VERSION 5.8 ;
BUSBITCHARS "[]" ;
DIVIDERCHAR "/" ;
UNITS
    DATABASE MICRONS 1000 ;
END UNITS

VIA PLL_COUNTER_DCO_PHYS_via1_2_2200_440_1_5_410_410
  VIARULE via1Array ;
  CUTSIZE 0.19 0.19 ;
  LAYERS Metal1 Via1 Metal2 ;
  CUTSPACING 0.22 0.22 ;
  ENCLOSURE 0.05 0.125 0.005 0.05 ;
  ROWCOL 1 5 ;
END PLL_COUNTER_DCO_PHYS_via1_2_2200_440_1_5_410_410

VIA PLL_COUNTER_DCO_PHYS_via2_3_2200_440_1_5_410_410
  VIARULE via2Array ;
  CUTSIZE 0.19 0.19 ;
  LAYERS Metal2 Via2 Metal3 ;
  CUTSPACING 0.22 0.22 ;
  ENCLOSURE 0.005 0.05 0.05 0.005 ;
  ROWCOL 1 5 ;
END PLL_COUNTER_DCO_PHYS_via2_3_2200_440_1_5_410_410

VIA PLL_COUNTER_DCO_PHYS_via3_4_2200_440_1_5_410_410
  VIARULE via3Array ;
  CUTSIZE 0.19 0.19 ;
  LAYERS Metal3 Via3 Metal4 ;
  CUTSPACING 0.22 0.22 ;
  ENCLOSURE 0.05 0.005 0.005 0.05 ;
  ROWCOL 1 5 ;
END PLL_COUNTER_DCO_PHYS_via3_4_2200_440_1_5_410_410

VIA PLL_COUNTER_DCO_PHYS_via4_5_2200_440_1_5_410_410
  VIARULE via4Array ;
  CUTSIZE 0.19 0.19 ;
  LAYERS Metal4 Via4 Metal5 ;
  CUTSPACING 0.22 0.22 ;
  ENCLOSURE 0.005 0.05 0.05 0.005 ;
  ROWCOL 1 5 ;
END PLL_COUNTER_DCO_PHYS_via4_5_2200_440_1_5_410_410

VIA PLL_COUNTER_DCO_PHYS_via5_6_2200_440_1_2_840_840
  VIARULE viaTop1Array ;
  CUTSIZE 0.42 0.42 ;
  LAYERS Metal5 TopVia1 TopMetal1 ;
  CUTSPACING 0.42 0.42 ;
  ENCLOSURE 0.1 0.1 0.47 0.42 ;
  ROWCOL 1 2 ;
END PLL_COUNTER_DCO_PHYS_via5_6_2200_440_1_2_840_840

VIA PLL_COUNTER_DCO_PHYS_via6_7_5000_5000_2_2_1960_1960
  VIARULE viaTop2Array ;
  CUTSIZE 0.9 0.9 ;
  LAYERS TopMetal1 TopVia2 TopMetal2 ;
  CUTSPACING 1.06 1.06 ;
  ENCLOSURE 1.07 0.5 0.5 1.07 ;
  ROWCOL 2 2 ;
END PLL_COUNTER_DCO_PHYS_via6_7_5000_5000_2_2_1960_1960

VIA PLL_COUNTER_DCO_PHYS_via6_7_5000_2200_1_2_1960_1960
  VIARULE viaTop2Array ;
  CUTSIZE 0.9 0.9 ;
  LAYERS TopMetal1 TopVia2 TopMetal2 ;
  CUTSPACING 1.06 1.06 ;
  ENCLOSURE 1.07 0.5 0.5 0.65 ;
  ROWCOL 1 2 ;
END PLL_COUNTER_DCO_PHYS_via6_7_5000_2200_1_2_1960_1960

VIA PLL_COUNTER_DCO_PHYS_via6_7_2200_5000_2_1_1960_1960
  VIARULE viaTop2Array ;
  CUTSIZE 0.9 0.9 ;
  LAYERS TopMetal1 TopVia2 TopMetal2 ;
  CUTSPACING 1.06 1.06 ;
  ENCLOSURE 0.65 0.5 0.5 1.07 ;
  ROWCOL 2 1 ;
END PLL_COUNTER_DCO_PHYS_via6_7_2200_5000_2_1_1960_1960

VIA PLL_COUNTER_DCO_PHYS_via6_7_2200_2200_1_1_1960_1960
  VIARULE viaTop2Array ;
  CUTSIZE 0.9 0.9 ;
  LAYERS TopMetal1 TopVia2 TopMetal2 ;
  CUTSPACING 1.06 1.06 ;
  ENCLOSURE 0.65 0.5 0.5 0.65 ;
END PLL_COUNTER_DCO_PHYS_via6_7_2200_2200_1_1_1960_1960

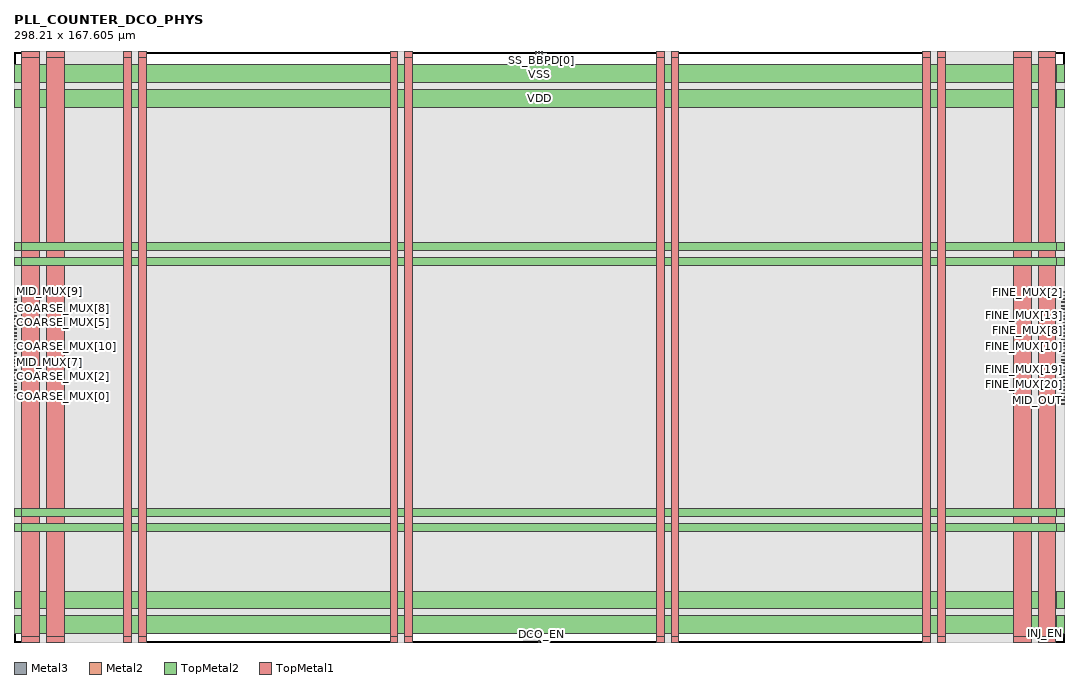
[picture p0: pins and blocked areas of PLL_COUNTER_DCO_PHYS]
MACRO PLL_COUNTER_DCO_PHYS
  FOREIGN PLL_COUNTER_DCO_PHYS 0 0 ;
  CLASS BLOCK ;
  SIZE 298.21 BY 167.605 ;
  PIN COARSE_MUX[0]
    DIRECTION INPUT ;
    USE SIGNAL ;
    PORT
      LAYER Metal3 ;
        RECT  0 69.5 0.72 69.7 ;
    END
  END COARSE_MUX[0]
  PIN COARSE_MUX[10]
    DIRECTION INPUT ;
    USE SIGNAL ;
    PORT
      LAYER Metal3 ;
        RECT  0 83.9 0.72 84.1 ;
    END
  END COARSE_MUX[10]
  PIN COARSE_MUX[11]
    DIRECTION INPUT ;
    USE SIGNAL ;
    PORT
      LAYER Metal3 ;
        RECT  0 76.22 0.72 76.42 ;
    END
  END COARSE_MUX[11]
  PIN COARSE_MUX[12]
    DIRECTION INPUT ;
    USE SIGNAL ;
    PORT
      LAYER Metal3 ;
        RECT  0 80.06 0.72 80.26 ;
    END
  END COARSE_MUX[12]
  PIN COARSE_MUX[13]
    DIRECTION INPUT ;
    USE SIGNAL ;
    PORT
      LAYER Metal3 ;
        RECT  0 72.38 0.72 72.58 ;
    END
  END COARSE_MUX[13]
  PIN COARSE_MUX[14]
    DIRECTION INPUT ;
    USE SIGNAL ;
    PORT
      LAYER Metal3 ;
        RECT  0 86.78 0.72 86.98 ;
    END
  END COARSE_MUX[14]
  PIN COARSE_MUX[1]
    DIRECTION INPUT ;
    USE SIGNAL ;
    PORT
      LAYER Metal3 ;
        RECT  0 87.74 0.72 87.94 ;
    END
  END COARSE_MUX[1]
  PIN COARSE_MUX[2]
    DIRECTION INPUT ;
    USE SIGNAL ;
    PORT
      LAYER Metal3 ;
        RECT  0 75.26 0.72 75.46 ;
    END
  END COARSE_MUX[2]
  PIN COARSE_MUX[3]
    DIRECTION INPUT ;
    USE SIGNAL ;
    PORT
      LAYER Metal3 ;
        RECT  0 88.7 0.72 88.9 ;
    END
  END COARSE_MUX[3]
  PIN COARSE_MUX[4]
    DIRECTION INPUT ;
    USE SIGNAL ;
    PORT
      LAYER Metal3 ;
        RECT  0 89.66 0.72 89.86 ;
    END
  END COARSE_MUX[4]
  PIN COARSE_MUX[5]
    DIRECTION INPUT ;
    USE SIGNAL ;
    PORT
      LAYER Metal3 ;
        RECT  0 90.62 0.72 90.82 ;
    END
  END COARSE_MUX[5]
  PIN COARSE_MUX[6]
    DIRECTION INPUT ;
    USE SIGNAL ;
    PORT
      LAYER Metal3 ;
        RECT  0 81.02 0.72 81.22 ;
    END
  END COARSE_MUX[6]
  PIN COARSE_MUX[7]
    DIRECTION INPUT ;
    USE SIGNAL ;
    PORT
      LAYER Metal3 ;
        RECT  0 74.3 0.72 74.5 ;
    END
  END COARSE_MUX[7]
  PIN COARSE_MUX[8]
    DIRECTION INPUT ;
    USE SIGNAL ;
    PORT
      LAYER Metal3 ;
        RECT  0 92.54 0.72 92.74 ;
    END
  END COARSE_MUX[8]
  PIN COARSE_MUX[9]
    DIRECTION INPUT ;
    USE SIGNAL ;
    PORT
      LAYER Metal3 ;
        RECT  0 85.82 0.72 86.02 ;
    END
  END COARSE_MUX[9]
  PIN DCO_EN
    DIRECTION INPUT ;
    USE SIGNAL ;
    PORT
      LAYER Metal2 ;
        RECT  149.84 0 150.04 0.72 ;
    END
  END DCO_EN
  PIN FINE_MUX[0]
    DIRECTION INPUT ;
    USE SIGNAL ;
    PORT
      LAYER Metal3 ;
        RECT  297.49 67.58 298.21 67.78 ;
    END
  END FINE_MUX[0]
  PIN FINE_MUX[10]
    DIRECTION INPUT ;
    USE SIGNAL ;
    PORT
      LAYER Metal3 ;
        RECT  297.49 83.9 298.21 84.1 ;
    END
  END FINE_MUX[10]
  PIN FINE_MUX[11]
    DIRECTION INPUT ;
    USE SIGNAL ;
    PORT
      LAYER Metal3 ;
        RECT  297.49 98.3 298.21 98.5 ;
    END
  END FINE_MUX[11]
  PIN FINE_MUX[12]
    DIRECTION INPUT ;
    USE SIGNAL ;
    PORT
      LAYER Metal3 ;
        RECT  297.49 96.38 298.21 96.58 ;
    END
  END FINE_MUX[12]
  PIN FINE_MUX[13]
    DIRECTION INPUT ;
    USE SIGNAL ;
    PORT
      LAYER Metal3 ;
        RECT  297.49 92.54 298.21 92.74 ;
    END
  END FINE_MUX[13]
  PIN FINE_MUX[14]
    DIRECTION INPUT ;
    USE SIGNAL ;
    PORT
      LAYER Metal3 ;
        RECT  297.49 84.86 298.21 85.06 ;
    END
  END FINE_MUX[14]
  PIN FINE_MUX[15]
    DIRECTION INPUT ;
    USE SIGNAL ;
    PORT
      LAYER Metal3 ;
        RECT  297.49 87.74 298.21 87.94 ;
    END
  END FINE_MUX[15]
  PIN FINE_MUX[16]
    DIRECTION INPUT ;
    USE SIGNAL ;
    PORT
      LAYER Metal3 ;
        RECT  297.49 79.1 298.21 79.3 ;
    END
  END FINE_MUX[16]
  PIN FINE_MUX[17]
    DIRECTION INPUT ;
    USE SIGNAL ;
    PORT
      LAYER Metal3 ;
        RECT  297.49 78.14 298.21 78.34 ;
    END
  END FINE_MUX[17]
  PIN FINE_MUX[18]
    DIRECTION INPUT ;
    USE SIGNAL ;
    PORT
      LAYER Metal3 ;
        RECT  297.49 93.5 298.21 93.7 ;
    END
  END FINE_MUX[18]
  PIN FINE_MUX[19]
    DIRECTION INPUT ;
    USE SIGNAL ;
    PORT
      LAYER Metal3 ;
        RECT  297.49 77.18 298.21 77.38 ;
    END
  END FINE_MUX[19]
  PIN FINE_MUX[1]
    DIRECTION INPUT ;
    USE SIGNAL ;
    PORT
      LAYER Metal3 ;
        RECT  297.49 76.22 298.21 76.42 ;
    END
  END FINE_MUX[1]
  PIN FINE_MUX[20]
    DIRECTION INPUT ;
    USE SIGNAL ;
    PORT
      LAYER Metal3 ;
        RECT  297.49 75.26 298.21 75.46 ;
    END
  END FINE_MUX[20]
  PIN FINE_MUX[21]
    DIRECTION INPUT ;
    USE SIGNAL ;
    PORT
      LAYER Metal3 ;
        RECT  297.49 86.78 298.21 86.98 ;
    END
  END FINE_MUX[21]
  PIN FINE_MUX[22]
    DIRECTION INPUT ;
    USE SIGNAL ;
    PORT
      LAYER Metal3 ;
        RECT  297.49 82.94 298.21 83.14 ;
    END
  END FINE_MUX[22]
  PIN FINE_MUX[23]
    DIRECTION INPUT ;
    USE SIGNAL ;
    PORT
      LAYER Metal3 ;
        RECT  297.49 94.46 298.21 94.66 ;
    END
  END FINE_MUX[23]
  PIN FINE_MUX[24]
    DIRECTION INPUT ;
    USE SIGNAL ;
    PORT
      LAYER Metal3 ;
        RECT  297.49 81.98 298.21 82.18 ;
    END
  END FINE_MUX[24]
  PIN FINE_MUX[25]
    DIRECTION INPUT ;
    USE SIGNAL ;
    PORT
      LAYER Metal3 ;
        RECT  297.49 97.34 298.21 97.54 ;
    END
  END FINE_MUX[25]
  PIN FINE_MUX[26]
    DIRECTION INPUT ;
    USE SIGNAL ;
    PORT
      LAYER Metal3 ;
        RECT  297.49 72.38 298.21 72.58 ;
    END
  END FINE_MUX[26]
  PIN FINE_MUX[27]
    DIRECTION INPUT ;
    USE SIGNAL ;
    PORT
      LAYER Metal3 ;
        RECT  297.49 71.42 298.21 71.62 ;
    END
  END FINE_MUX[27]
  PIN FINE_MUX[28]
    DIRECTION INPUT ;
    USE SIGNAL ;
    PORT
      LAYER Metal3 ;
        RECT  297.49 70.46 298.21 70.66 ;
    END
  END FINE_MUX[28]
  PIN FINE_MUX[29]
    DIRECTION INPUT ;
    USE SIGNAL ;
    PORT
      LAYER Metal3 ;
        RECT  297.49 88.7 298.21 88.9 ;
    END
  END FINE_MUX[29]
  PIN FINE_MUX[2]
    DIRECTION INPUT ;
    USE SIGNAL ;
    PORT
      LAYER Metal3 ;
        RECT  297.49 99.26 298.21 99.46 ;
    END
  END FINE_MUX[2]
  PIN FINE_MUX[30]
    DIRECTION INPUT ;
    USE SIGNAL ;
    PORT
      LAYER Metal3 ;
        RECT  297.49 80.06 298.21 80.26 ;
    END
  END FINE_MUX[30]
  PIN FINE_MUX[3]
    DIRECTION INPUT ;
    USE SIGNAL ;
    PORT
      LAYER Metal3 ;
        RECT  297.49 95.42 298.21 95.62 ;
    END
  END FINE_MUX[3]
  PIN FINE_MUX[4]
    DIRECTION INPUT ;
    USE SIGNAL ;
    PORT
      LAYER Metal3 ;
        RECT  297.49 89.66 298.21 89.86 ;
    END
  END FINE_MUX[4]
  PIN FINE_MUX[5]
    DIRECTION INPUT ;
    USE SIGNAL ;
    PORT
      LAYER Metal3 ;
        RECT  297.49 81.02 298.21 81.22 ;
    END
  END FINE_MUX[5]
  PIN FINE_MUX[6]
    DIRECTION INPUT ;
    USE SIGNAL ;
    PORT
      LAYER Metal3 ;
        RECT  297.49 69.5 298.21 69.7 ;
    END
  END FINE_MUX[6]
  PIN FINE_MUX[7]
    DIRECTION INPUT ;
    USE SIGNAL ;
    PORT
      LAYER Metal3 ;
        RECT  297.49 73.34 298.21 73.54 ;
    END
  END FINE_MUX[7]
  PIN FINE_MUX[8]
    DIRECTION INPUT ;
    USE SIGNAL ;
    PORT
      LAYER Metal3 ;
        RECT  297.49 90.62 298.21 90.82 ;
    END
  END FINE_MUX[8]
  PIN FINE_MUX[9]
    DIRECTION INPUT ;
    USE SIGNAL ;
    PORT
      LAYER Metal3 ;
        RECT  297.49 74.3 298.21 74.5 ;
    END
  END FINE_MUX[9]
  PIN INJ_EN
    DIRECTION INPUT ;
    USE SIGNAL ;
    PORT
      LAYER Metal3 ;
        RECT  297.49 2.3 298.21 2.5 ;
    END
  END INJ_EN
  PIN MID_MUX[0]
    DIRECTION INPUT ;
    USE SIGNAL ;
    PORT
      LAYER Metal3 ;
        RECT  0 70.46 0.72 70.66 ;
    END
  END MID_MUX[0]
  PIN MID_MUX[10]
    DIRECTION INPUT ;
    USE SIGNAL ;
    PORT
      LAYER Metal3 ;
        RECT  0 91.58 0.72 91.78 ;
    END
  END MID_MUX[10]
  PIN MID_MUX[11]
    DIRECTION INPUT ;
    USE SIGNAL ;
    PORT
      LAYER Metal3 ;
        RECT  0 71.42 0.72 71.62 ;
    END
  END MID_MUX[11]
  PIN MID_MUX[12]
    DIRECTION INPUT ;
    USE SIGNAL ;
    PORT
      LAYER Metal3 ;
        RECT  0 95.42 0.72 95.62 ;
    END
  END MID_MUX[12]
  PIN MID_MUX[13]
    DIRECTION INPUT ;
    USE SIGNAL ;
    PORT
      LAYER Metal3 ;
        RECT  0 79.1 0.72 79.3 ;
    END
  END MID_MUX[13]
  PIN MID_MUX[14]
    DIRECTION INPUT ;
    USE SIGNAL ;
    PORT
      LAYER Metal3 ;
        RECT  0 84.86 0.72 85.06 ;
    END
  END MID_MUX[14]
  PIN MID_MUX[1]
    DIRECTION INPUT ;
    USE SIGNAL ;
    PORT
      LAYER Metal3 ;
        RECT  0 73.34 0.72 73.54 ;
    END
  END MID_MUX[1]
  PIN MID_MUX[2]
    DIRECTION INPUT ;
    USE SIGNAL ;
    PORT
      LAYER Metal3 ;
        RECT  0 93.5 0.72 93.7 ;
    END
  END MID_MUX[2]
  PIN MID_MUX[3]
    DIRECTION INPUT ;
    USE SIGNAL ;
    PORT
      LAYER Metal3 ;
        RECT  0 78.14 0.72 78.34 ;
    END
  END MID_MUX[3]
  PIN MID_MUX[4]
    DIRECTION INPUT ;
    USE SIGNAL ;
    PORT
      LAYER Metal3 ;
        RECT  0 96.38 0.72 96.58 ;
    END
  END MID_MUX[4]
  PIN MID_MUX[5]
    DIRECTION INPUT ;
    USE SIGNAL ;
    PORT
      LAYER Metal3 ;
        RECT  0 94.46 0.72 94.66 ;
    END
  END MID_MUX[5]
  PIN MID_MUX[6]
    DIRECTION INPUT ;
    USE SIGNAL ;
    PORT
      LAYER Metal3 ;
        RECT  0 82.94 0.72 83.14 ;
    END
  END MID_MUX[6]
  PIN MID_MUX[7]
    DIRECTION INPUT ;
    USE SIGNAL ;
    PORT
      LAYER Metal3 ;
        RECT  0 77.18 0.72 77.38 ;
    END
  END MID_MUX[7]
  PIN MID_MUX[8]
    DIRECTION INPUT ;
    USE SIGNAL ;
    PORT
      LAYER Metal3 ;
        RECT  0 81.98 0.72 82.18 ;
    END
  END MID_MUX[8]
  PIN MID_MUX[9]
    DIRECTION INPUT ;
    USE SIGNAL ;
    PORT
      LAYER Metal3 ;
        RECT  0 97.34 0.72 97.54 ;
    END
  END MID_MUX[9]
  PIN MID_OUT
    DIRECTION OUTPUT ;
    USE SIGNAL ;
    PORT
      LAYER Metal3 ;
        RECT  297.49 68.54 298.21 68.74 ;
    END
  END MID_OUT
  PIN OUT
    DIRECTION OUTPUT ;
    USE SIGNAL ;
    PORT
      LAYER Metal3 ;
        RECT  297.49 85.82 298.21 86.02 ;
    END
  END OUT
  PIN INJ_EDGE
    DIRECTION OUTPUT ;
    USE SIGNAL ;
    PORT
      LAYER Metal3 ;
        RECT  297.49 91.58 298.21 91.78 ;
    END
  END INJ_EDGE
  PIN REF
    DIRECTION INPUT ;
    USE SIGNAL ;
    PORT
      LAYER Metal2 ;
        RECT  149 0 149.2 0.72 ;
    END
  END REF
  PIN SS_BBPD[0]
    DIRECTION OUTPUT ;
    USE SIGNAL ;
    PORT
      LAYER Metal2 ;
        RECT  149.84 166.885 150.04 167.605 ;
    END
  END SS_BBPD[0]
  PIN SS_BBPD[1]
    DIRECTION OUTPUT ;
    USE SIGNAL ;
    PORT
      LAYER Metal2 ;
        RECT  149 166.885 149.2 167.605 ;
    END
  END SS_BBPD[1]
  PIN TICK
    DIRECTION INPUT ;
    USE SIGNAL ;
    PORT
      LAYER Metal2 ;
        RECT  148.16 166.885 148.36 167.605 ;
    END
  END TICK
  PIN VSS
    DIRECTION INOUT ;
    USE GROUND ;
    PORT
      LAYER TopMetal2 ;
        RECT  296.21 111.2 298.21 113.4 ;
        RECT  0 111.2 2 113.4 ;
        RECT  0 111.2 298.21 113.4 ;
        RECT  296.21 35.6 298.21 37.8 ;
        RECT  0 35.6 2 37.8 ;
        RECT  0 35.6 298.21 37.8 ;
      LAYER TopMetal1 ;
        RECT  262.22 165.965 264.42 167.605 ;
        RECT  262.22 0 264.42 1.64 ;
        RECT  262.22 0 264.42 167.605 ;
        RECT  186.62 165.965 188.82 167.605 ;
        RECT  186.62 0 188.82 1.64 ;
        RECT  186.62 0 188.82 167.605 ;
        RECT  111.02 165.965 113.22 167.605 ;
        RECT  111.02 0 113.22 1.64 ;
        RECT  111.02 0 113.22 167.605 ;
        RECT  35.42 165.965 37.62 167.605 ;
        RECT  35.42 0 37.62 1.64 ;
        RECT  35.42 0 37.62 167.605 ;
      LAYER TopMetal2 ;
        RECT  296.21 158.92 298.21 163.92 ;
        RECT  0 158.92 2 163.92 ;
        RECT  0 158.92 298.21 163.92 ;
        RECT  296.21 2.4 298.21 7.4 ;
        RECT  0 2.4 2 7.4 ;
        RECT  0 2.4 298.21 7.4 ;
      LAYER TopMetal1 ;
        RECT  290.86 165.965 295.86 167.605 ;
        RECT  290.86 0 295.86 1.64 ;
        RECT  290.86 0 295.86 167.605 ;
        RECT  2.22 165.965 7.22 167.605 ;
        RECT  2.22 0 7.22 1.64 ;
        RECT  2.22 0 7.22 167.605 ;
    END
  END VSS
  PIN VDD
    DIRECTION INOUT ;
    USE POWER ;
    PORT
      LAYER TopMetal2 ;
        RECT  296.21 107 298.21 109.2 ;
        RECT  0 107 2 109.2 ;
        RECT  0 107 298.21 109.2 ;
        RECT  296.21 31.4 298.21 33.6 ;
        RECT  0 31.4 2 33.6 ;
        RECT  0 31.4 298.21 33.6 ;
      LAYER TopMetal1 ;
        RECT  258.02 165.965 260.22 167.605 ;
        RECT  258.02 0 260.22 1.64 ;
        RECT  258.02 0 260.22 167.605 ;
        RECT  182.42 165.965 184.62 167.605 ;
        RECT  182.42 0 184.62 1.64 ;
        RECT  182.42 0 184.62 167.605 ;
        RECT  106.82 165.965 109.02 167.605 ;
        RECT  106.82 0 109.02 1.64 ;
        RECT  106.82 0 109.02 167.605 ;
        RECT  31.22 165.965 33.42 167.605 ;
        RECT  31.22 0 33.42 1.64 ;
        RECT  31.22 0 33.42 167.605 ;
      LAYER TopMetal2 ;
        RECT  296.21 151.92 298.21 156.92 ;
        RECT  0 151.92 2 156.92 ;
        RECT  0 151.92 298.21 156.92 ;
        RECT  296.21 9.4 298.21 14.4 ;
        RECT  0 9.4 2 14.4 ;
        RECT  0 9.4 298.21 14.4 ;
      LAYER TopMetal1 ;
        RECT  283.86 165.965 288.86 167.605 ;
        RECT  283.86 0 288.86 1.64 ;
        RECT  283.86 0 288.86 167.605 ;
        RECT  9.22 165.965 14.22 167.605 ;
        RECT  9.22 0 14.22 1.64 ;
        RECT  9.22 0 14.22 167.605 ;
    END
  END VDD
  OBS
    LAYER Metal1 ;
     RECT  18.72 18.68 279.36 147.64 ;
    LAYER Metal2 ;
     RECT  144.8 0.38 148.78 0.48 ;
     RECT  186.8 18.755 188.64 20.505 ;
     RECT  57.965 20.49 58.165 20.54 ;
     RECT  70.965 20.53 71.165 20.54 ;
     RECT  186.8 20.505 190.755 20.54 ;
     RECT  216.475 20.505 216.675 20.54 ;
     RECT  250.885 20.51 251.085 20.54 ;
     RECT  262.4 18.755 264.24 20.54 ;
     RECT  57.44 20.54 58.165 20.55 ;
     RECT  262.4 20.54 268.06 20.55 ;
     RECT  166.64 20.54 175.24 20.555 ;
     RECT  204.44 20.54 206.53 20.555 ;
     RECT  57.44 20.55 59.32 21.02 ;
     RECT  69.62 20.54 71.165 21.02 ;
     RECT  144.8 0.48 150.04 21.02 ;
     RECT  203.95 20.555 206.53 21.02 ;
     RECT  216.475 20.54 219.34 21.02 ;
     RECT  57.44 21.02 71.165 21.03 ;
     RECT  166.03 20.555 175.24 21.03 ;
     RECT  242.24 20.54 251.085 21.03 ;
     RECT  186.8 20.54 192.04 21.5 ;
     RECT  203.95 21.02 219.34 21.5 ;
     RECT  242.24 21.03 252.1 21.98 ;
     RECT  262.4 20.55 268.48 22.46 ;
     RECT  35.6 18.755 37.44 22.535 ;
     RECT  111.2 18.755 113.04 22.535 ;
     RECT  166.03 21.03 176.92 22.535 ;
     RECT  186.8 21.5 219.34 22.535 ;
     RECT  240.56 21.98 252.1 22.535 ;
     RECT  262.4 22.46 278.98 22.535 ;
     RECT  144.8 21.02 152.14 22.94 ;
     RECT  31.4 22.535 37.44 22.95 ;
     RECT  57.44 21.03 71.5 23.42 ;
     RECT  140.18 22.94 154.24 23.42 ;
     RECT  166.03 22.535 219.34 23.42 ;
     RECT  140.18 23.42 219.34 23.43 ;
     RECT  57.44 23.42 73.6 23.665 ;
     RECT  31.4 22.95 47.14 23.9 ;
     RECT  57.44 23.665 75.28 23.9 ;
     RECT  140.18 23.43 228.58 23.9 ;
     RECT  240.56 22.535 278.98 23.9 ;
     RECT  26.78 23.9 75.28 24 ;
     RECT  26.36 24 75.28 24.385 ;
     RECT  25.805 24.385 75.28 24.69 ;
     RECT  25.805 24.69 75.405 24.86 ;
     RECT  140.18 23.9 278.98 24.86 ;
     RECT  21.74 24.86 75.405 25.34 ;
     RECT  21.74 25.34 76.96 25.82 ;
     RECT  21.74 25.82 77.38 27.02 ;
     RECT  21.32 27.02 77.38 27.26 ;
     RECT  138.08 24.86 278.98 27.74 ;
     RECT  134.3 27.74 278.98 27.98 ;
     RECT  21.32 27.26 81.16 28.7 ;
     RECT  21.32 28.7 82 30.62 ;
     RECT  21.32 30.62 82.155 31.1 ;
     RECT  133.04 27.98 278.98 31.1 ;
     RECT  132.2 31.1 278.98 32.06 ;
     RECT  131.36 32.06 278.98 32.735 ;
     RECT  131.36 32.735 235.3 32.74 ;
     RECT  131.88 32.74 235.3 33.22 ;
     RECT  245.18 32.735 278.98 35.14 ;
     RECT  21.32 31.1 83.68 35.66 ;
     RECT  21.32 35.66 84.52 35.665 ;
     RECT  21.32 35.665 85.575 35.9 ;
     RECT  19.64 35.9 86.62 38.78 ;
     RECT  1.16 36.86 1.36 40.22 ;
     RECT  19.64 38.78 87.04 40.7 ;
     RECT  296.84 39.26 297.04 43.1 ;
     RECT  133.25 33.22 235.3 43.275 ;
     RECT  245.18 35.14 273.1 43.275 ;
     RECT  133.25 43.275 273.1 45.02 ;
     RECT  133.25 45.02 274.36 46.47 ;
     RECT  133.25 46.47 276.67 47.04 ;
     RECT  19.64 40.7 87.46 47.42 ;
     RECT  19.64 47.42 87.88 48.38 ;
     RECT  294.32 43.1 297.04 50.3 ;
     RECT  133.25 47.04 276.04 50.5 ;
     RECT  19.64 48.38 88.3 54.14 ;
     RECT  290.12 50.3 297.04 54.62 ;
     RECT  18.8 54.14 88.3 54.915 ;
     RECT  107 22.535 113.04 54.935 ;
     RECT  133.25 50.5 274.78 54.985 ;
     RECT  18.8 54.915 89.98 55.1 ;
     RECT  107 54.935 115.82 55.1 ;
     RECT  132.335 54.985 274.78 56.06 ;
     RECT  107 55.1 117.28 56.54 ;
     RECT  107 56.54 118.75 57.02 ;
     RECT  107 57.02 122.445 57.03 ;
     RECT  132.2 56.06 274.78 57.03 ;
     RECT  18.8 55.1 90.4 57.5 ;
     RECT  18.8 57.5 91.66 57.815 ;
     RECT  107 57.03 274.78 58.285 ;
     RECT  105.11 58.285 274.78 58.305 ;
     RECT  18.8 57.815 92.92 61.35 ;
     RECT  102.66 58.305 274.78 61.35 ;
     RECT  18.8 61.35 274.78 65.38 ;
     RECT  1.16 40.22 5.56 66.14 ;
     RECT  289.7 54.62 297.04 68.54 ;
     RECT  1.16 66.14 5.98 71.42 ;
     RECT  289.7 68.54 297.46 71.62 ;
     RECT  290.54 71.62 297.46 75.5 ;
     RECT  18.8 65.38 274.15 76.7 ;
     RECT  18.8 76.7 275.62 78.14 ;
     RECT  1.16 71.42 6.4 78.82 ;
     RECT  18.8 78.14 276.04 79.58 ;
     RECT  1.16 78.82 5.98 80.26 ;
     RECT  18.8 79.58 277.09 80.26 ;
     RECT  18.8 80.26 276.46 81.7 ;
     RECT  18.8 81.7 276.04 84.1 ;
     RECT  19.22 84.1 276.04 86.02 ;
     RECT  290.54 75.5 297.88 86.02 ;
     RECT  290.54 86.02 296.62 86.78 ;
     RECT  5.36 80.26 5.98 86.98 ;
     RECT  5.78 86.98 5.98 87.46 ;
     RECT  290.12 86.78 296.62 88.7 ;
     RECT  19.64 86.02 276.04 93.22 ;
     RECT  289.7 88.7 296.62 95.14 ;
     RECT  289.7 95.14 296.2 99.46 ;
     RECT  20.48 93.22 276.04 100.22 ;
     RECT  20.48 100.22 276.46 104.54 ;
     RECT  289.7 99.46 291.16 107.14 ;
     RECT  289.7 107.14 290.32 107.62 ;
     RECT  289.7 107.62 289.9 108.58 ;
     RECT  20.48 104.54 277.72 109.06 ;
     RECT  23 109.06 277.72 109.53 ;
     RECT  24.68 109.53 277.72 109.54 ;
     RECT  24.815 109.54 277.72 110.79 ;
     RECT  24.815 110.79 278.56 111.335 ;
     RECT  25.52 111.335 278.56 111.36 ;
     RECT  25.52 111.36 278.14 111.46 ;
     RECT  31.4 111.46 278.14 113.38 ;
     RECT  31.4 113.38 276.46 126.525 ;
     RECT  47.36 126.525 276.46 127.3 ;
     RECT  49.04 127.3 276.46 128.74 ;
     RECT  49.25 128.74 276.46 129.7 ;
     RECT  49.25 129.7 50.5 130.66 ;
     RECT  60.38 129.7 276.46 130.66 ;
     RECT  60.38 130.66 119.59 131.14 ;
     RECT  60.885 131.14 119.59 131.62 ;
     RECT  60.885 131.62 113.04 132.58 ;
     RECT  129.26 130.66 276.46 132.58 ;
     RECT  62.255 132.58 113.04 133.54 ;
     RECT  135.72 132.58 276.46 133.78 ;
     RECT  62.255 133.54 66.46 134.015 ;
     RECT  62.9 134.015 66.46 134.02 ;
     RECT  65.605 134.02 66.46 134.07 ;
     RECT  66.26 134.07 66.46 134.135 ;
     RECT  135.77 133.78 276.46 135.46 ;
     RECT  136.4 135.46 276.46 136.23 ;
     RECT  136.4 136.23 276.88 136.9 ;
     RECT  141.02 136.9 276.88 137.18 ;
     RECT  141.02 137.18 277.09 137.66 ;
     RECT  141.02 137.66 278.56 137.86 ;
     RECT  76.76 133.54 113.04 138.34 ;
     RECT  77.18 138.34 113.04 138.72 ;
     RECT  104.48 138.72 113.04 138.82 ;
     RECT  143.035 137.86 278.56 139.1 ;
     RECT  77.18 138.72 92.775 139.78 ;
     RECT  77.18 139.78 88.72 140.74 ;
     RECT  77.18 140.74 85.78 141.6 ;
     RECT  77.18 141.6 84.52 141.7 ;
     RECT  143.035 139.1 278.98 141.7 ;
     RECT  179.87 141.7 210.94 142.17 ;
     RECT  143.035 141.7 165.16 142.18 ;
     RECT  182.6 142.17 197.5 142.18 ;
     RECT  220.82 141.7 276.88 142.18 ;
     RECT  242.24 142.18 267.01 142.32 ;
     RECT  143.035 142.18 151.3 142.53 ;
     RECT  161.18 142.18 161.38 142.65 ;
     RECT  251.06 142.32 267.01 142.65 ;
     RECT  182.6 142.18 193.72 142.66 ;
     RECT  210.74 142.17 210.94 142.66 ;
     RECT  220.82 142.18 232.36 143.14 ;
     RECT  31.4 126.525 37.44 143.785 ;
     RECT  107 138.82 113.04 143.785 ;
     RECT  182.6 142.66 188.64 143.785 ;
     RECT  251.06 142.65 264.24 143.785 ;
     RECT  251.06 143.785 252.1 144.48 ;
     RECT  251.06 144.48 251.68 144.58 ;
     RECT  143.96 142.53 151.3 145.06 ;
     RECT  251.48 144.58 251.68 145.78 ;
     RECT  224.6 143.14 232.36 145.92 ;
     RECT  225.44 145.92 232.36 146.02 ;
     RECT  225.44 146.02 226.9 146.5 ;
     RECT  35.6 143.785 37.44 147.565 ;
     RECT  111.2 143.785 113.04 147.565 ;
     RECT  186.8 143.785 188.64 147.565 ;
     RECT  262.4 143.785 264.24 147.565 ;
     RECT  148.16 145.06 151.3 167.04 ;
     RECT  150.26 167.04 151.3 167.14 ;
    LAYER Metal3 ;
     RECT  1.16 36.86 5.36 37.06 ;
     RECT  4.94 46.94 5.36 47.14 ;
     RECT  0.42 69.5 5.78 97.54 ;
     RECT  5.36 36.86 18.8 47.14 ;
     RECT  18.8 36.86 19.64 54.34 ;
     RECT  19.64 35.9 20.06 54.34 ;
     RECT  5.78 66.14 20.06 97.54 ;
     RECT  20.06 35.9 20.48 97.54 ;
     RECT  20.48 35.9 21.74 109.06 ;
     RECT  21.74 24.86 26.36 109.06 ;
     RECT  26.36 24.38 31.355 109.06 ;
     RECT  31.355 22.58 35.555 143.74 ;
     RECT  35.555 18.8 37.485 147.52 ;
     RECT  37.485 23.42 49.88 126.34 ;
     RECT  49.88 23.42 59.12 130.66 ;
     RECT  59.12 21.02 60.38 130.66 ;
     RECT  60.38 21.02 63.32 131.14 ;
     RECT  63.32 21.02 68.14 131.62 ;
     RECT  68.14 21.5 71.5 131.62 ;
     RECT  71.5 23.9 71.72 131.62 ;
     RECT  71.72 23.9 75.28 133.54 ;
     RECT  75.28 25.34 75.405 133.54 ;
     RECT  75.405 25.82 76.76 133.54 ;
     RECT  76.76 25.82 77.18 135.94 ;
     RECT  77.18 25.82 77.38 141.7 ;
     RECT  77.38 27.26 81.16 141.7 ;
     RECT  81.16 28.7 82 141.7 ;
     RECT  82 31.58 82.21 141.7 ;
     RECT  82.21 31.58 82.84 111.94 ;
     RECT  82.84 35.9 83.26 111.94 ;
     RECT  83.26 36.38 83.68 111.94 ;
     RECT  82.21 122.3 85.78 141.7 ;
     RECT  83.68 37.82 86.62 111.94 ;
     RECT  86.62 47.42 86.83 111.94 ;
     RECT  86.83 57.02 89.98 111.94 ;
     RECT  89.98 57.5 91.66 111.94 ;
     RECT  85.78 122.3 92.775 139.78 ;
     RECT  91.66 61.82 93.34 111.94 ;
     RECT  92.775 122.3 93.98 138.82 ;
     RECT  93.34 61.82 104.48 103.78 ;
     RECT  104.48 58.46 104.9 103.78 ;
     RECT  93.98 113.66 104.9 138.82 ;
     RECT  104.9 58.46 106.955 138.82 ;
     RECT  106.955 22.58 111.155 143.74 ;
     RECT  111.155 18.8 113.085 147.52 ;
     RECT  113.085 57.02 115.6 131.62 ;
     RECT  115.6 118.46 119.59 131.62 ;
     RECT  115.6 57.02 122.445 105.22 ;
     RECT  119.59 118.46 123.58 130.66 ;
     RECT  122.445 57.5 125.615 105.22 ;
     RECT  125.615 57.5 127.58 107.62 ;
     RECT  127.58 57.5 128.42 108.1 ;
     RECT  123.58 123.74 129.26 130.66 ;
     RECT  131.36 32.54 131.88 32.74 ;
     RECT  131.88 32.54 132.41 33.22 ;
     RECT  132.41 32.06 133.25 33.22 ;
     RECT  128.42 57.5 133.46 110.98 ;
     RECT  133.25 32.06 134.3 45.7 ;
     RECT  133.46 55.58 134.3 110.98 ;
     RECT  134.3 55.58 134.72 111.46 ;
     RECT  129.26 123.74 134.72 132.58 ;
     RECT  134.72 55.58 136.4 132.58 ;
     RECT  134.3 27.74 139.34 45.7 ;
     RECT  136.4 55.58 139.34 136.9 ;
     RECT  139.34 27.74 140.18 136.9 ;
     RECT  140.18 22.94 141.02 136.9 ;
     RECT  141.02 22.94 143.035 137.86 ;
     RECT  143.035 22.94 143.96 142.18 ;
     RECT  143.96 22.94 149.2 145.06 ;
     RECT  149.2 22.94 151.94 141.7 ;
     RECT  151.94 21.02 156.065 141.7 ;
     RECT  156.065 88.7 161.18 141.7 ;
     RECT  161.18 88.7 165.16 142.18 ;
     RECT  156.065 21.02 166.015 78.82 ;
     RECT  165.16 88.7 166.015 141.7 ;
     RECT  166.015 21.02 167.26 141.7 ;
     RECT  167.26 21.5 176.92 141.7 ;
     RECT  176.92 22.58 182.555 141.7 ;
     RECT  182.555 22.58 186.755 143.74 ;
     RECT  186.755 18.8 188.685 147.52 ;
     RECT  188.685 20.54 191.2 142.66 ;
     RECT  191.2 21.5 205.06 142.66 ;
     RECT  205.06 23.9 210.94 142.66 ;
     RECT  210.94 23.9 220.82 141.7 ;
     RECT  220.82 23.9 224.6 143.14 ;
     RECT  224.6 23.9 232.36 146.02 ;
     RECT  232.36 23.9 240.56 142.18 ;
     RECT  240.56 21.98 242.76 142.18 ;
     RECT  242.76 21.02 244.54 142.18 ;
     RECT  244.54 21.5 251.06 142.18 ;
     RECT  251.06 21.5 252.1 144.58 ;
     RECT  252.1 22.58 262.355 143.74 ;
     RECT  262.355 18.8 264.285 147.52 ;
     RECT  264.285 21.02 268.48 142.18 ;
     RECT  268.48 22.46 268.9 142.18 ;
     RECT  268.9 133.82 272.26 142.18 ;
     RECT  268.9 22.46 273.1 123.94 ;
     RECT  273.1 32.54 274.78 123.94 ;
     RECT  274.78 32.54 276.04 123.46 ;
     RECT  272.26 133.82 276.46 141.7 ;
     RECT  276.46 136.7 276.88 141.7 ;
     RECT  276.04 32.54 278.14 113.38 ;
     RECT  278.14 32.54 278.56 111.46 ;
     RECT  276.88 137.66 278.56 141.7 ;
     RECT  273.1 22.46 278.98 22.66 ;
     RECT  278.56 32.54 278.98 108.58 ;
     RECT  278.56 141.5 278.98 141.7 ;
     RECT  278.98 39.26 289.9 108.58 ;
     RECT  289.9 39.26 290.32 107.62 ;
     RECT  290.32 59.9 291.16 107.14 ;
     RECT  290.32 39.26 294.52 43.3 ;
     RECT  291.16 59.9 296.2 99.46 ;
     RECT  294.52 39.26 297.04 39.46 ;
     RECT  296.2 67.58 297.78 99.46 ;
    LAYER Metal4 ;
     RECT  35.6 18.755 37.44 22.535 ;
     RECT  111.2 18.755 113.04 22.535 ;
     RECT  186.8 18.755 188.64 22.535 ;
     RECT  262.4 18.755 264.24 22.535 ;
     RECT  31.4 22.535 37.44 28.22 ;
     RECT  51.98 27.74 52.18 29.86 ;
     RECT  219.14 24.86 219.34 33.7 ;
     RECT  70.46 34.94 70.66 40.42 ;
     RECT  30.98 28.22 37.44 42.34 ;
     RECT  128.84 58.46 129.04 63.46 ;
     RECT  87.68 62.3 87.88 66.34 ;
     RECT  20.06 62.78 20.26 69.5 ;
     RECT  107 22.535 113.04 72.86 ;
     RECT  182.6 22.535 188.64 73.35 ;
     RECT  176.72 73.35 188.64 73.92 ;
     RECT  128.42 66.62 128.62 74.02 ;
     RECT  289.7 73.34 289.9 76.22 ;
     RECT  19.64 69.5 20.26 77.86 ;
     RECT  289.7 76.22 297.04 77.86 ;
     RECT  20.06 77.86 20.26 78.14 ;
     RECT  31.4 42.34 37.44 78.14 ;
     RECT  151.1 73.34 151.3 78.15 ;
     RECT  147.74 78.15 151.3 78.72 ;
     RECT  131.36 77.66 131.56 78.82 ;
     RECT  151.1 78.72 151.3 78.82 ;
     RECT  258.2 22.535 264.24 81.02 ;
     RECT  20.06 78.14 37.44 81.22 ;
     RECT  99.02 72.86 113.04 81.22 ;
     RECT  20.06 81.22 20.26 82.66 ;
     RECT  257.78 81.02 264.24 85.06 ;
     RECT  182.6 73.92 188.64 87.74 ;
     RECT  289.7 77.86 289.9 89.86 ;
     RECT  182.6 87.74 189.94 90.34 ;
     RECT  31.4 81.22 37.44 92.54 ;
     RECT  274.16 91.1 274.36 92.74 ;
     RECT  29.3 92.54 37.44 93.02 ;
     RECT  49.46 88.7 49.66 93.02 ;
     RECT  146.9 90.14 147.1 95.14 ;
     RECT  28.04 93.02 37.44 98.98 ;
     RECT  214.52 97.82 214.72 98.98 ;
     RECT  29.3 98.98 37.44 100.7 ;
     RECT  49.46 93.02 55.96 100.7 ;
     RECT  29.3 100.7 55.96 101.38 ;
     RECT  226.7 93.02 226.9 101.38 ;
     RECT  29.3 101.38 47.14 103.78 ;
     RECT  258.2 85.06 264.24 104.06 ;
     RECT  144.38 99.26 144.58 108.86 ;
     RECT  31.4 103.78 47.14 110.5 ;
     RECT  258.2 104.06 272.68 111.26 ;
     RECT  144.38 108.86 148.36 118.66 ;
     RECT  254.84 111.26 272.68 122.5 ;
     RECT  254.84 122.5 271 123.94 ;
     RECT  144.38 118.66 144.58 127.3 ;
     RECT  79.7 95.42 79.9 130.46 ;
     RECT  234.68 116.54 234.88 130.46 ;
     RECT  233.84 130.46 234.88 131.62 ;
     RECT  79.7 130.46 81.16 132.1 ;
     RECT  233.84 131.62 234.04 132.1 ;
     RECT  254.84 123.94 264.24 140.74 ;
     RECT  31.4 110.5 37.44 143.785 ;
     RECT  107 81.22 113.04 143.785 ;
     RECT  182.6 90.34 188.64 143.785 ;
     RECT  258.2 140.74 264.24 143.785 ;
     RECT  35.6 143.785 37.44 147.565 ;
     RECT  111.2 143.785 113.04 147.565 ;
     RECT  186.8 143.785 188.64 147.565 ;
     RECT  262.4 143.785 264.24 147.565 ;
    LAYER Metal5 ;
     RECT  31.355 22.37 35.555 143.95 ;
     RECT  35.555 18.59 37.485 147.73 ;
     RECT  106.955 22.37 111.155 143.95 ;
     RECT  111.155 18.59 113.085 147.73 ;
     RECT  131.36 77.66 147.74 77.86 ;
     RECT  147.74 77.66 176.72 78.82 ;
     RECT  176.72 73.82 182.555 78.82 ;
     RECT  182.555 22.37 186.755 143.95 ;
     RECT  186.755 18.59 188.685 147.73 ;
     RECT  188.685 73.82 258.155 78.82 ;
     RECT  258.155 22.37 262.355 143.95 ;
     RECT  262.355 18.59 264.285 147.73 ;
     RECT  264.285 73.82 289.9 78.82 ;
     RECT  289.9 77.66 297.04 77.86 ;
    LAYER TopMetal1 ;
     RECT  2.22 0 37.62 167.605 ;
     RECT  106.82 0 113.22 167.605 ;
     RECT  182.42 0 188.82 167.605 ;
     RECT  258.02 0 295.86 167.605 ;
    LAYER TopMetal2 ;
     RECT  0 2.4 298.21 163.92 ;
  END
END PLL_COUNTER_DCO_PHYS
END LIBRARY
